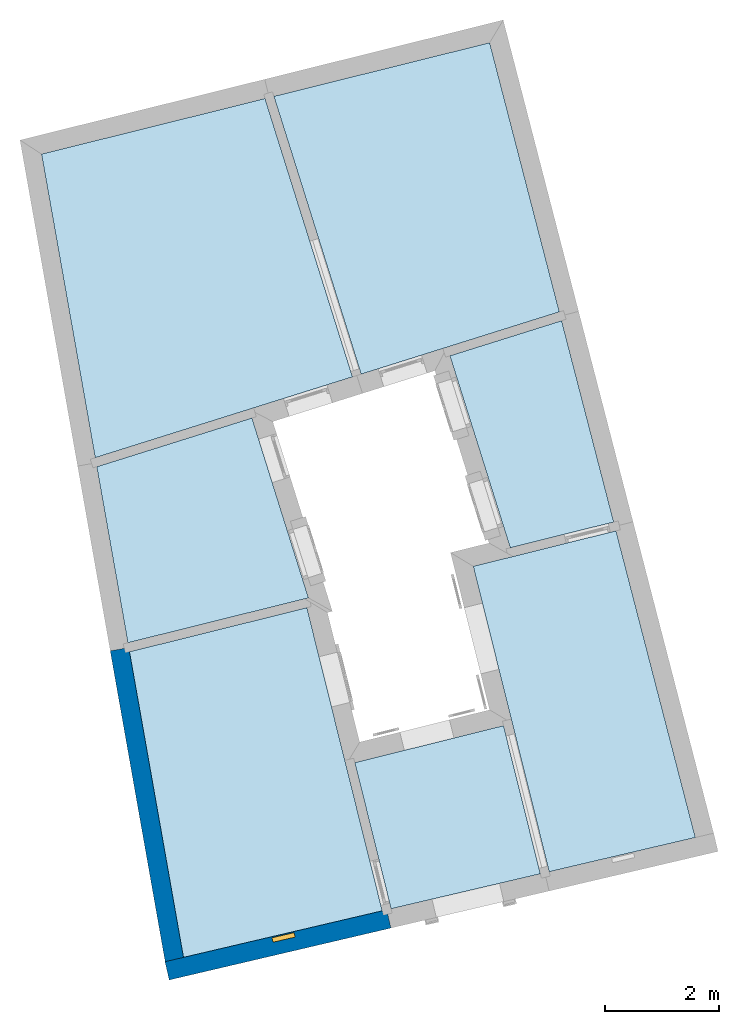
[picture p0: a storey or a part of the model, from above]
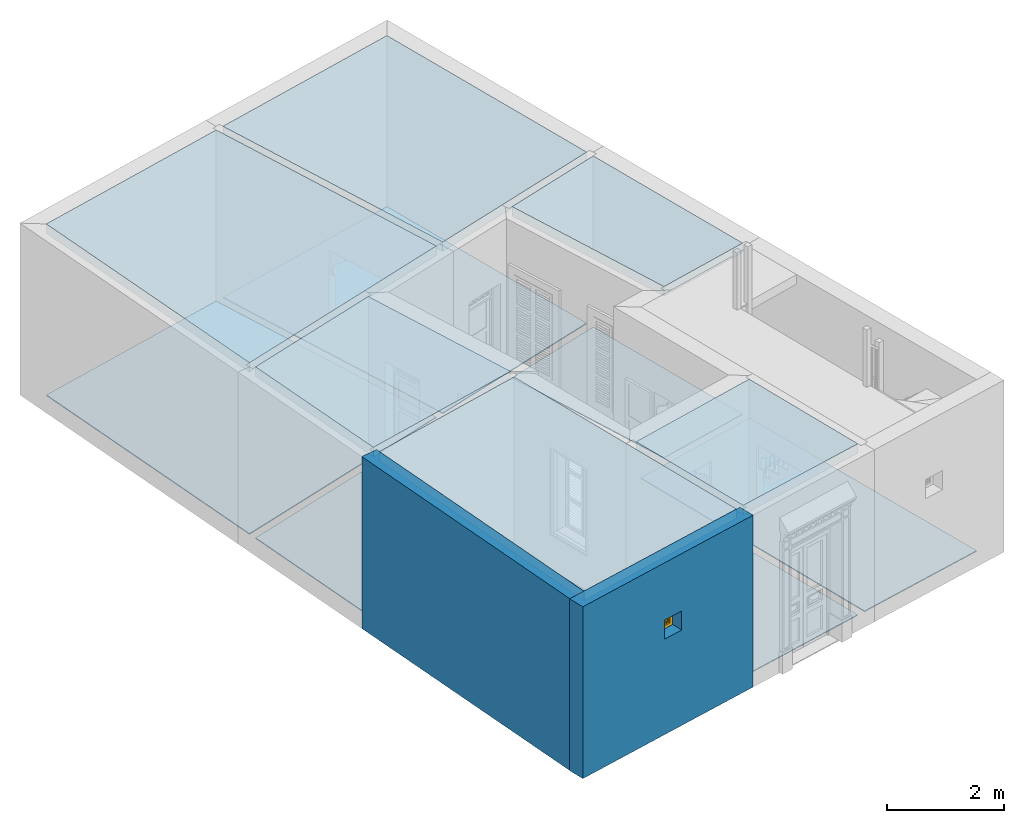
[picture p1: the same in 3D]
Properties of the parts of a building model (IFC4)

# File
Description: ViewDefinition[DesignTransferView]
File name: molior-ifc.pl
Time: 2024-09-23T22:30:47
Author: bruno
Written by: File::IFC-0.01

# IfcProject, Molior Project
Document: Building plot-0; plot-0 0; plot-0 1; Building plot-0 NORTH; Building plot-0 SOUTH; Building plot-0 WEST; Building plot-0 EAST; Building plot-0 LOCATION; Building plot-1; plot-1 0; plot-1 1; plot-1 2; Building plot-1 NORTH; Building plot-1 SOUTH; Building plot-1 WEST; Building plot-1 EAST; Building plot-1 LOCATION; Building plot-2; plot-2 0; plot-2 1; Building plot-2 NORTH; Building plot-2 SOUTH; Building plot-2 WEST; Building plot-2 EAST; Building plot-2 LOCATION; Building plot-3; plot-3 0; plot-3 1; Building plot-3 NORTH; Building plot-3 SOUTH; Building plot-3 WEST; Building plot-3 EAST; Building plot-3 LOCATION; Building plot-4; plot-4 0; plot-4 1; plot-4 2; Building plot-4 NORTH; Building plot-4 SOUTH; Building plot-4 WEST; Building plot-4 EAST; Building plot-4 LOCATION; Building plot-5; plot-5 0; plot-5 1; Building plot-5 NORTH; Building plot-5 SOUTH; Building plot-5 WEST; Building plot-5 EAST; Building plot-5 LOCATION; Building plot-6; plot-6 0; plot-6 1; Building plot-6 NORTH; Building plot-6 SOUTH; Building plot-6 WEST; Building plot-6 EAST; Building plot-6 LOCATION; Building plot-7; plot-7 0; plot-7 1; plot-7 2; Building plot-7 NORTH; Building plot-7 SOUTH; Building plot-7 WEST; Building plot-7 EAST; Building plot-7 LOCATION; Building plot-8; plot-8 0; plot-8 1; Building plot-8 NORTH; Building plot-8 SOUTH; Building plot-8 WEST; Building plot-8 EAST; Building plot-8 LOCATION; Building plot-9; plot-9 0; plot-9 1; Building plot-9 NORTH; Building plot-9 SOUTH; Building plot-9 WEST; Building plot-9 EAST; Building plot-9 LOCATION; Building plot-10; plot-10 0; plot-10 1; Building plot-10 NORTH; Building plot-10 SOUTH; Building plot-10 WEST; Building plot-10 EAST; Building plot-10 LOCATION

# IfcBuildingStorey (25)
Name | In | Elevation (m)
plot-0 0 | Building plot-0 | 0
plot-0 1 | Building plot-0 | 3.6
plot-1 0 | Building plot-1 | 0
plot-1 1 | Building plot-1 | 2.7
plot-1 2 | Building plot-1 | 5.4
plot-10 0 | Building plot-10 | 0
plot-10 1 | Building plot-10 | 2.7
plot-2 0 | Building plot-2 | 0
plot-2 1 | Building plot-2 | 2.85
plot-3 0 | Building plot-3 | 0
plot-3 1 | Building plot-3 | 3.3
plot-4 0 | Building plot-4 | 0
plot-4 1 | Building plot-4 | 2.7
plot-4 2 | Building plot-4 | 5.4
plot-5 0 | Building plot-5 | 0
plot-5 1 | Building plot-5 | 3.45
plot-6 0 | Building plot-6 | 0
plot-6 1 | Building plot-6 | 3.6
plot-7 0 | Building plot-7 | 0
plot-7 1 | Building plot-7 | 3
plot-7 2 | Building plot-7 | 5.7
plot-8 0 | Building plot-8 | 0
plot-8 1 | Building plot-8 | 3
plot-9 0 | Building plot-9 | 0
plot-9 1 | Building plot-9 | 2.85

# IfcSpace (168)
Name | In | LongName | PredefinedType | NetFloorArea (m2) | Height (m) | NetVolume (m3)
Bedroom | plot-0 0 | Bedroom 0 rl | INTERNAL | 18.6033 | 3.38 | 62.8793
Circulation | plot-0 0 | Circulation 0 rrrl | INTERNAL | 7.18052 | 3.38 | 24.2702
Sahn | plot-0 0 | Sahn 0 rrrr | EXTERNAL | 7.24061 | 3.38 | 24.4733
Bedroom | plot-0 0 | Bedroom 0 lll | INTERNAL | 9.86909 | 3.38 | 33.3575
Sahn | plot-0 0 | Sahn 0 llrr | EXTERNAL | 11.4049 | 3.38 | 38.5485
Living | plot-0 0 | Living 0 lrr | INTERNAL | 23.1098 | 3.38 | 78.1113
Toilet | plot-0 0 | Toilet 0 llrl | INTERNAL | 7.06812 | 3.38 | 23.8902
Kitchen | plot-0 0 | Kitchen 0 lrl | INTERNAL | 18.9053 | 3.38 | 63.9
Stair | plot-0 0 | Stair 0 rrl | INTERNAL | 14.5007 | 3.38 | 49.0124
Toilet | plot-0 1 | Toilet 1 llrl | INTERNAL | 7.06812 | 2.48 | 17.5289
Sahn | plot-0 1 | Sahn 1 lll | EXTERNAL | 9.86909 | 2.48 | 24.4753
Sahn | plot-0 1 | Sahn 1 rl | EXTERNAL | 18.6033 | 2.48 | 46.1363
Stair | plot-0 1 | Stair 1 rrl | INTERNAL | 14.5007 | 2.48 | 35.9617
Sahn | plot-0 1 | Sahn 1 rrrl | EXTERNAL | 7.18052 | 2.48 | 17.8077
Sahn | plot-0 1 | Sahn 1 lrrr | EXTERNAL | 10.2465 | 2.48 | 25.4112
Bedroom | plot-0 1 | Bedroom 1 lrl | INTERNAL | 18.9053 | 2.48 | 46.8852
Bedroom | plot-0 1 | Bedroom 1 lrrl | INTERNAL | 12.1528 | 2.48 | 30.139
Stair | plot-1 0 | Stair 0 rl | INTERNAL | 13.5087 | 2.48 | 33.5016
Bedroom | plot-1 0 | Bedroom 0 rr | INTERNAL | 15.269 | 2.48 | 37.8671
Sahn | plot-1 0 | Sahn 0 llll | EXTERNAL | 16.588 | 2.48 | 41.1382
Circulation | plot-1 0 | Circulation 0 llr | INTERNAL | 15.6253 | 2.48 | 38.7507
Bedroom | plot-1 0 | Bedroom 0 lllrr | INTERNAL | 7.61929 | 2.48 | 18.8958
Living | plot-1 0 | Living 0 lr | INTERNAL | 20.2347 | 2.48 | 50.1821
Toilet | plot-1 0 | Toilet 0 lllrl | INTERNAL | 7.64653 | 2.48 | 18.9634
Kitchen | plot-1 1 | Kitchen 1 lllrl | INTERNAL | 7.64653 | 2.48 | 18.9634
Bedroom | plot-1 1 | Bedroom 1 lllrr | INTERNAL | 7.61929 | 2.48 | 18.8958
Living | plot-1 1 | Living 1 lr | INTERNAL | 20.2347 | 2.48 | 50.1821
Stair | plot-1 1 | Stair 1 rl | INTERNAL | 13.5087 | 2.48 | 33.5016
Sahn | plot-1 1 | Sahn 1 rr | EXTERNAL | 15.269 | 2.48 | 37.8671
Sahn | plot-1 1 | Sahn 1 llr | EXTERNAL | 15.6253 | 2.48 | 38.7507
Sahn | plot-1 2 | Sahn 2 lllrl | EXTERNAL | 7.64653 | 2.48 | 18.9634
Sahn | plot-1 2 | Sahn 2 lllrr | EXTERNAL | 7.61929 | 2.48 | 18.8958
Sahn | plot-1 2 | Sahn 2 lr | EXTERNAL | 20.2347 | 2.48 | 50.1821
Stair | plot-1 2 | Stair 2 rl | INTERNAL | 13.5087 | 2.48 | 33.5016
Circulation | plot-10 0 | Circulation 0 lrlll | INTERNAL | 7.03777 | 2.48 | 17.4537
Toilet | plot-10 0 | Toilet 0 lrllr | INTERNAL | 8.32168 | 2.48 | 20.6378
Kitchen | plot-10 0 | Kitchen 0 lll | INTERNAL | 12.7723 | 2.48 | 31.6752
Bedroom | plot-10 0 | Bedroom 0 llr | INTERNAL | 13.3682 | 2.48 | 33.1531
Sahn | plot-10 0 | Sahn 0 lrlr | EXTERNAL | 14.0717 | 2.48 | 34.8977
Stair | plot-10 0 | Stair 0 lrr | INTERNAL | 10.8846 | 2.48 | 26.9937
Living | plot-10 0 | Living 0 r | INTERNAL | 23.0062 | 2.48 | 57.0555
Bedroom | plot-10 1 | Bedroom 1 lll | INTERNAL | 12.7723 | 2.48 | 31.6752
Sahn | plot-10 1 | Sahn 1 llr | EXTERNAL | 13.3682 | 2.48 | 33.1531
Stair | plot-10 1 | Stair 1 lrr | INTERNAL | 10.8846 | 2.48 | 26.9937
Living | plot-10 1 | Living 1 r | INTERNAL | 23.0062 | 2.48 | 57.0555
Sahn | plot-10 1 | Sahn 1 lrlll | EXTERNAL | 7.03777 | 2.48 | 17.4537
Sahn | plot-10 1 | Sahn 1 lrllr | EXTERNAL | 8.32168 | 2.48 | 20.6378
Sahn | plot-2 0 | Sahn 0 llll | EXTERNAL | 19.2153 | 2.63 | 50.5361
Stair | plot-2 0 | Stair 0 llrl | INTERNAL | 12.6232 | 2.63 | 33.1991
Kitchen | plot-2 0 | Kitchen 0 llrr | INTERNAL | 14.1375 | 2.63 | 37.1816
Toilet | plot-2 0 | Toilet 0 lllr | INTERNAL | 8.14435 | 2.63 | 21.4196
Circulation | plot-2 0 | Circulation 0 rl | INTERNAL | 18.3057 | 2.63 | 48.1441
Bedroom | plot-2 0 | Bedroom 0 rrl | INTERNAL | 5.66446 | 2.63 | 14.8975
Bedroom | plot-2 0 | Bedroom 0 rrr | INTERNAL | 11.2214 | 2.63 | 29.5124
Living | plot-2 0 | Living 0 lr | INTERNAL | 30.7366 | 2.63 | 80.8373
Sahn | plot-2 1 | Sahn 1 lllr | EXTERNAL | 8.14435 | 2.48 | 20.198
Sahn | plot-2 1 | Sahn 1 lrl | EXTERNAL | 18.1389 | 2.48 | 44.9844
Sahn | plot-2 1 | Sahn 1 llrr | EXTERNAL | 14.1375 | 2.48 | 35.061
Toilet | plot-2 1 | Toilet 1 lrrl | INTERNAL | 5.53656 | 2.48 | 13.7307
Bedroom | plot-2 1 | Bedroom 1 lrrr | INTERNAL | 5.7305 | 2.48 | 14.2116
Stair | plot-2 1 | Stair 1 llrl | INTERNAL | 12.6232 | 2.48 | 31.3056
Bedroom | plot-2 1 | Bedroom 1 rl | INTERNAL | 18.3057 | 2.48 | 45.3982
Bedroom | plot-2 1 | Bedroom 1 rr | INTERNAL | 17.3011 | 2.48 | 42.9068
Sahn | plot-3 0 | Sahn 0 rrll | EXTERNAL | 12.8553 | 3.08 | 39.5942
Living | plot-3 0 | Living 0 rrr | INTERNAL | 19.1901 | 3.08 | 59.1056
Kitchen | plot-3 0 | Kitchen 0 rrlrl | INTERNAL | 6.68529 | 3.08 | 20.5907
Bedroom | plot-3 0 | Bedroom 0 rl | INTERNAL | 17.7381 | 3.08 | 54.6334
Toilet | plot-3 0 | Toilet 0 rrlrr | INTERNAL | 6.24022 | 3.08 | 19.2199
Stair | plot-3 0 | Stair 0 ll | INTERNAL | 11.7867 | 3.08 | 36.303
Circulation | plot-3 0 | Circulation 0 lr | INTERNAL | 15.885 | 3.08 | 48.9257
Sahn | plot-3 1 | Sahn 1 rrlrl | EXTERNAL | 6.68529 | 2.48 | 16.5795
Circulation | plot-3 1 | Circulation 1 rrlrr | INTERNAL | 6.24022 | 2.48 | 15.4757
Stair | plot-3 1 | Stair 1 ll | INTERNAL | 11.7867 | 2.48 | 29.231
Sahn | plot-3 1 | Sahn 1 rl | EXTERNAL | 17.7381 | 2.48 | 43.9905
Bedroom | plot-3 1 | Bedroom 1 lrl | INTERNAL | 11.3691 | 2.48 | 28.1954
Sahn | plot-3 1 | Sahn 1 rrr | EXTERNAL | 19.1901 | 2.48 | 47.5916
Bedroom | plot-3 1 | Bedroom 1 lrr | INTERNAL | 4.17706 | 2.48 | 10.3591
Circulation | plot-4 0 | Circulation 0 lllllr | INTERNAL | 5.30634 | 2.48 | 13.1597
Toilet | plot-4 0 | Toilet 0 llllr | INTERNAL | 7.85125 | 2.48 | 19.4711
Kitchen | plot-4 0 | Kitchen 0 rl | INTERNAL | 14.8165 | 2.48 | 36.7448
Living | plot-4 0 | Living 0 rr | INTERNAL | 23.3067 | 2.48 | 57.8006
Sahn | plot-4 0 | Sahn 0 lllr | EXTERNAL | 20.2577 | 2.48 | 50.239
Stair | plot-4 0 | Stair 0 lrl | INTERNAL | 11.632 | 2.48 | 28.8474
Toilet | plot-4 0 | Toilet 0 llllll | INTERNAL | 6.71825 | 2.48 | 16.6613
Bedroom | plot-4 0 | Bedroom 0 llr | INTERNAL | 19.073 | 2.48 | 47.3011
Bedroom | plot-4 0 | Bedroom 0 lrr | INTERNAL | 13.8841 | 2.48 | 34.4327
Bedroom | plot-4 1 | Bedroom 1 rl | INTERNAL | 14.8165 | 2.48 | 36.7448
Living | plot-4 1 | Living 1 rr | INTERNAL | 23.3067 | 2.48 | 57.8006
Sahn | plot-4 1 | Sahn 1 lllllr | EXTERNAL | 5.30634 | 2.48 | 13.1597
Sahn | plot-4 1 | Sahn 1 llllr | EXTERNAL | 7.85125 | 2.48 | 19.4711
Sahn | plot-4 1 | Sahn 1 llllll | EXTERNAL | 6.71825 | 2.48 | 16.6613
Stair | plot-4 1 | Stair 1 lrl | INTERNAL | 11.632 | 2.48 | 28.8474
Sahn | plot-4 1 | Sahn 1 lrr | EXTERNAL | 13.8841 | 2.48 | 34.4327
Sahn | plot-4 1 | Sahn 1 llr | EXTERNAL | 19.073 | 2.48 | 47.3011
Bedroom | plot-4 2 | Bedroom 2 rl | INTERNAL | 14.8165 | 2.48 | 36.7448
Sahn | plot-4 2 | Sahn 2 rr | EXTERNAL | 23.3067 | 2.48 | 57.8006
Stair | plot-4 2 | Stair 2 lrl | INTERNAL | 11.632 | 2.48 | 28.8474
Kitchen | plot-5 0 | Kitchen 0 rlll | INTERNAL | 8.13273 | 3.23 | 26.2687
Stair | plot-5 0 | Stair 0 rr | INTERNAL | 15.9944 | 3.23 | 51.662
Sahn | plot-5 0 | Sahn 0 rllr | EXTERNAL | 7.58685 | 3.23 | 24.5055
Bedroom | plot-5 0 | Bedroom 0 ll | INTERNAL | 14.4939 | 3.23 | 46.8152
Circulation | plot-5 0 | Circulation 0 lr | INTERNAL | 13.1461 | 3.23 | 42.462
Living | plot-5 0 | Living 0 rlr | INTERNAL | 18.2042 | 3.23 | 58.7996
Sahn | plot-5 1 | Sahn 1 lrl | EXTERNAL | 6.59347 | 2.48 | 16.3518
Toilet | plot-5 1 | Toilet 1 lrr | INTERNAL | 6.14669 | 2.48 | 15.2438
Sahn | plot-5 1 | Sahn 1 ll | EXTERNAL | 14.4939 | 2.48 | 35.9448
Sahn | plot-5 1 | Sahn 1 rlll | EXTERNAL | 8.13273 | 2.48 | 20.1692
Stair | plot-5 1 | Stair 1 rr | INTERNAL | 15.9944 | 2.48 | 39.6662
Bedroom | plot-5 1 | Bedroom 1 rlr | INTERNAL | 18.2042 | 2.48 | 45.1464
Sahn | plot-6 0 | Sahn 0 llll | EXTERNAL | 12.5452 | 3.38 | 42.4029
Bedroom | plot-6 0 | Bedroom 0 rl | INTERNAL | 11.0626 | 3.38 | 37.3915
Bedroom | plot-6 0 | Bedroom 0 rr | INTERNAL | 11.039 | 3.38 | 37.3117
Toilet | plot-6 0 | Toilet 0 lllr | INTERNAL | 7.05394 | 3.38 | 23.8423
Stair | plot-6 0 | Stair 0 lr | INTERNAL | 13.6163 | 3.38 | 46.0231
Circulation | plot-6 0 | Circulation 0 llr | INTERNAL | 18.765 | 3.38 | 63.4256
Bedroom | plot-6 1 | Bedroom 1 rl | INTERNAL | 11.0626 | 2.48 | 27.4352
Sahn | plot-6 1 | Sahn 1 rr | EXTERNAL | 11.039 | 2.48 | 27.3766
Kitchen | plot-6 1 | Kitchen 1 lllr | INTERNAL | 7.05394 | 2.48 | 17.4938
Stair | plot-6 1 | Stair 1 lr | INTERNAL | 13.6163 | 2.48 | 33.7685
Living | plot-6 1 | Living 1 llr | INTERNAL | 18.765 | 2.48 | 46.5371
Toilet | plot-7 0 | Toilet 0 rlrl | INTERNAL | 3.98221 | 2.78 | 11.0705
Toilet | plot-7 0 | Toilet 0 rlrr | INTERNAL | 5.86152 | 2.78 | 16.295
Sahn | plot-7 0 | Sahn 0 rll | EXTERNAL | 8.14408 | 2.78 | 22.6406
Circulation | plot-7 0 | Circulation 0 lrl | INTERNAL | 12.4041 | 2.78 | 34.4834
Kitchen | plot-7 0 | Kitchen 0 lrr | INTERNAL | 12.9413 | 2.78 | 35.9769
Stair | plot-7 0 | Stair 0 ll | INTERNAL | 10.553 | 2.78 | 29.3373
Living | plot-7 0 | Living 0 rr | INTERNAL | 14.6748 | 2.78 | 40.7959
Sahn | plot-7 1 | Sahn 1 rlrl | EXTERNAL | 3.98221 | 2.48 | 9.87588
Sahn | plot-7 1 | Sahn 1 rlrr | EXTERNAL | 5.86152 | 2.48 | 14.5366
Bedroom | plot-7 1 | Bedroom 1 lrl | INTERNAL | 12.4041 | 2.48 | 30.7622
Sahn | plot-7 1 | Sahn 1 lrr | EXTERNAL | 12.9413 | 2.48 | 32.0945
Stair | plot-7 1 | Stair 1 ll | INTERNAL | 10.553 | 2.48 | 26.1714
Sahn | plot-7 1 | Sahn 1 rr | EXTERNAL | 14.6748 | 2.48 | 36.3935
Stair | plot-7 2 | Stair 2 ll | INTERNAL | 10.553 | 2.48 | 26.1714
Bedroom | plot-7 2 | Bedroom 2 lrl | INTERNAL | 12.4041 | 2.48 | 30.7622
Living | plot-8 0 | Living 0 ll | INTERNAL | 17.9999 | 2.78 | 50.0396
Sahn | plot-8 0 | Sahn 0 rrrl | EXTERNAL | 18.5938 | 2.78 | 51.6907
Bedroom | plot-8 0 | Bedroom 0 rrrrr | INTERNAL | 11.8045 | 2.78 | 32.8164
Kitchen | plot-8 0 | Kitchen 0 lr | INTERNAL | 14.4188 | 2.78 | 40.0843
Toilet | plot-8 0 | Toilet 0 rll | INTERNAL | 10.7814 | 2.78 | 29.9723
Circulation | plot-8 0 | Circulation 0 rlr | INTERNAL | 12.9269 | 2.78 | 35.9368
Stair | plot-8 0 | Stair 0 rrl | INTERNAL | 12.6416 | 2.78 | 35.1437
Bedroom | plot-8 0 | Bedroom 0 rrrrl | INTERNAL | 7.50273 | 2.78 | 20.8576
Sahn | plot-8 1 | Sahn 1 rll | EXTERNAL | 10.7814 | 2.48 | 26.7379
Sahn | plot-8 1 | Sahn 1 rlr | EXTERNAL | 12.9269 | 2.48 | 32.0587
Stair | plot-8 1 | Stair 1 rrl | INTERNAL | 12.6416 | 2.48 | 31.3512
Sahn | plot-8 1 | Sahn 1 rrrrl | EXTERNAL | 7.50273 | 2.48 | 18.6068
Sahn | plot-8 1 | Sahn 1 rrrrr | EXTERNAL | 11.8045 | 2.48 | 29.2751
Bedroom | plot-8 1 | Bedroom 1 ll | INTERNAL | 17.9999 | 2.48 | 44.6397
Bedroom | plot-8 1 | Bedroom 1 lr | INTERNAL | 14.4188 | 2.48 | 35.7587
Bedroom | plot-9 0 | Bedroom 0 lrl | INTERNAL | 15.7746 | 2.63 | 41.4872
Bedroom | plot-9 0 | Bedroom 0 lrrl | INTERNAL | 6.73831 | 2.63 | 17.7218
Sahn | plot-9 0 | Sahn 0 lrrr | EXTERNAL | 9.66377 | 2.63 | 25.4157
Sahn | plot-9 0 | Sahn 0 lll | EXTERNAL | 11.3479 | 2.63 | 29.8449
Living | plot-9 0 | Living 0 rl | INTERNAL | 26.9561 | 2.63 | 70.8944
Kitchen | plot-9 0 | Kitchen 0 rr | INTERNAL | 22.585 | 2.63 | 59.3986
Toilet | plot-9 0 | Toilet 0 llrl | INTERNAL | 11.2217 | 2.63 | 29.5132
Stair | plot-9 0 | Stair 0 llrr | INTERNAL | 10.0608 | 2.63 | 26.4598
Sahn | plot-9 1 | Sahn 1 rll | EXTERNAL | 9.74117 | 2.48 | 24.1581
Bedroom | plot-9 1 | Bedroom 1 rlrl | INTERNAL | 8.31016 | 2.48 | 20.6092
Circulation | plot-9 1 | Circulation 1 rlrrl | INTERNAL | 3.32315 | 2.48 | 8.24141
Bedroom | plot-9 1 | Bedroom 1 lrrl | INTERNAL | 6.73831 | 2.48 | 16.711
Bedroom | plot-9 1 | Bedroom 1 llrl | INTERNAL | 11.2217 | 2.48 | 27.8299
Stair | plot-9 1 | Stair 1 llrr | INTERNAL | 10.0608 | 2.48 | 24.9507
Sahn | plot-9 1 | Sahn 1 rrl | EXTERNAL | 11.4975 | 2.48 | 28.5139
Circulation | plot-9 1 | Circulation 1 rrr | INTERNAL | 10.5731 | 2.48 | 26.2212
Sahn | plot-9 1 | Sahn 1 lrl | EXTERNAL | 15.7746 | 2.48 | 39.121
Bedroom | plot-9 1 | Bedroom 1 rlrrr | INTERNAL | 4.0163 | 2.48 | 9.96043

# IfcAnnotation: DRAWING (80)
EPset_Drawing - HasUnderlay: no; HasLinework: yes; HasAnnotation: yes; GlobalReferencing: yes; Stylesheet: drawings/assets/default.css; Markers: drawings/assets/markers.svg; Symbols: drawings/assets/symbols.svg; Patterns: drawings/assets/patterns.svg; ShadingStyles: drawings/assets/shading_styles.json; CurrentShadingStyle: Blender Default
Name | Document | TargetView | Scale | HumanScale | PositionX | PositionY | Group | Include
plot-0 0 | drawings/plot-0 0.svg drawings/plot-0 0.svg | PLAN_VIEW | 1/100 | 1:100 | 30 | 30 | plot-0 0
plot-0 1 | drawings/plot-0 1.svg drawings/plot-0 1.svg | PLAN_VIEW | 1/100 | 1:100 | 198.725 | 30 | plot-0 1
Building plot-0 NORTH | drawings/Building plot-0 NORTH.svg drawings/Building plot-0 NORTH.svg | ELEVATION_VIEW | 1/100 | 1:100 | 30 | 252.284 | Building plot-0 NORTH | IfcTypeProduct, IfcProduct, location="Building plot-0"
Building plot-0 SOUTH | drawings/Building plot-0 SOUTH.svg drawings/Building plot-0 SOUTH.svg | ELEVATION_VIEW | 1/100 | 1:100 | 198.725 | 252.284 | Building plot-0 SOUTH | IfcTypeProduct, IfcProduct, location="Building plot-0"
Building plot-0 WEST | drawings/Building plot-0 WEST.svg drawings/Building plot-0 WEST.svg | ELEVATION_VIEW | 1/100 | 1:100 | 367.45 | 252.284 | Building plot-0 WEST | IfcTypeProduct, IfcProduct, location="Building plot-0"
Building plot-0 EAST | drawings/Building plot-0 EAST.svg drawings/Building plot-0 EAST.svg | ELEVATION_VIEW | 1/100 | 1:100 | 579.733 | 252.284 | Building plot-0 EAST | IfcTypeProduct, IfcProduct, location="Building plot-0"
Building plot-0 LOCATION | drawings/Building plot-0 LOCATION.svg drawings/Building plot-0 LOCATION.svg | PLAN_VIEW | 1/1000 | 1:1000 | 792.017 | 252.284 | Building plot-0 LOCATION | IfcSite + IfcRoof, IfcWall, IfcSlab, location="Building plot-0"
plot-1 0 | drawings/plot-1 0.svg drawings/plot-1 0.svg | PLAN_VIEW | 1/100 | 1:100 | 30 | 30 | plot-1 0
plot-1 1 | drawings/plot-1 1.svg drawings/plot-1 1.svg | PLAN_VIEW | 1/100 | 1:100 | 202.963 | 30 | plot-1 1
plot-1 2 | drawings/plot-1 2.svg drawings/plot-1 2.svg | PLAN_VIEW | 1/100 | 1:100 | 375.926 | 30 | plot-1 2
Building plot-1 NORTH | drawings/Building plot-1 NORTH.svg drawings/Building plot-1 NORTH.svg | ELEVATION_VIEW | 1/100 | 1:100 | 30 | 221.306 | Building plot-1 NORTH | IfcTypeProduct, IfcProduct, location="Building plot-1"
Building plot-1 SOUTH | drawings/Building plot-1 SOUTH.svg drawings/Building plot-1 SOUTH.svg | ELEVATION_VIEW | 1/100 | 1:100 | 202.963 | 221.306 | Building plot-1 SOUTH | IfcTypeProduct, IfcProduct, location="Building plot-1"
Building plot-1 WEST | drawings/Building plot-1 WEST.svg drawings/Building plot-1 WEST.svg | ELEVATION_VIEW | 1/100 | 1:100 | 375.926 | 221.306 | Building plot-1 WEST | IfcTypeProduct, IfcProduct, location="Building plot-1"
Building plot-1 EAST | drawings/Building plot-1 EAST.svg drawings/Building plot-1 EAST.svg | ELEVATION_VIEW | 1/100 | 1:100 | 557.232 | 221.306 | Building plot-1 EAST | IfcTypeProduct, IfcProduct, location="Building plot-1"
Building plot-1 LOCATION | drawings/Building plot-1 LOCATION.svg drawings/Building plot-1 LOCATION.svg | PLAN_VIEW | 1/1000 | 1:1000 | 738.538 | 221.306 | Building plot-1 LOCATION | IfcSite + IfcRoof, IfcWall, IfcSlab, location="Building plot-1"
plot-2 0 | drawings/plot-2 0.svg drawings/plot-2 0.svg | PLAN_VIEW | 1/100 | 1:100 | 30 | 30 | plot-2 0
plot-2 1 | drawings/plot-2 1.svg drawings/plot-2 1.svg | PLAN_VIEW | 1/100 | 1:100 | 207.942 | 30 | plot-2 1
Building plot-2 NORTH | drawings/Building plot-2 NORTH.svg drawings/Building plot-2 NORTH.svg | ELEVATION_VIEW | 1/100 | 1:100 | 30 | 245.056 | Building plot-2 NORTH | IfcTypeProduct, IfcProduct, location="Building plot-2"
Building plot-2 SOUTH | drawings/Building plot-2 SOUTH.svg drawings/Building plot-2 SOUTH.svg | ELEVATION_VIEW | 1/100 | 1:100 | 207.942 | 245.056 | Building plot-2 SOUTH | IfcTypeProduct, IfcProduct, location="Building plot-2"
Building plot-2 WEST | drawings/Building plot-2 WEST.svg drawings/Building plot-2 WEST.svg | ELEVATION_VIEW | 1/100 | 1:100 | 385.883 | 245.056 | Building plot-2 WEST | IfcTypeProduct, IfcProduct, location="Building plot-2"
Building plot-2 EAST | drawings/Building plot-2 EAST.svg drawings/Building plot-2 EAST.svg | ELEVATION_VIEW | 1/100 | 1:100 | 590.939 | 245.056 | Building plot-2 EAST | IfcTypeProduct, IfcProduct, location="Building plot-2"
Building plot-2 LOCATION | drawings/Building plot-2 LOCATION.svg drawings/Building plot-2 LOCATION.svg | PLAN_VIEW | 1/1000 | 1:1000 | 795.996 | 245.056 | Building plot-2 LOCATION | IfcSite + IfcRoof, IfcWall, IfcSlab, location="Building plot-2"
plot-3 0 | drawings/plot-3 0.svg drawings/plot-3 0.svg | PLAN_VIEW | 1/100 | 1:100 | 30 | 30 | plot-3 0
plot-3 1 | drawings/plot-3 1.svg drawings/plot-3 1.svg | PLAN_VIEW | 1/100 | 1:100 | 183.355 | 30 | plot-3 1
Building plot-3 NORTH | drawings/Building plot-3 NORTH.svg drawings/Building plot-3 NORTH.svg | ELEVATION_VIEW | 1/100 | 1:100 | 30 | 244.792 | Building plot-3 NORTH | IfcTypeProduct, IfcProduct, location="Building plot-3"
Building plot-3 SOUTH | drawings/Building plot-3 SOUTH.svg drawings/Building plot-3 SOUTH.svg | ELEVATION_VIEW | 1/100 | 1:100 | 183.355 | 244.792 | Building plot-3 SOUTH | IfcTypeProduct, IfcProduct, location="Building plot-3"
Building plot-3 WEST | drawings/Building plot-3 WEST.svg drawings/Building plot-3 WEST.svg | ELEVATION_VIEW | 1/100 | 1:100 | 336.71 | 244.792 | Building plot-3 WEST | IfcTypeProduct, IfcProduct, location="Building plot-3"
Building plot-3 EAST | drawings/Building plot-3 EAST.svg drawings/Building plot-3 EAST.svg | ELEVATION_VIEW | 1/100 | 1:100 | 541.501 | 244.792 | Building plot-3 EAST | IfcTypeProduct, IfcProduct, location="Building plot-3"
Building plot-3 LOCATION | drawings/Building plot-3 LOCATION.svg drawings/Building plot-3 LOCATION.svg | PLAN_VIEW | 1/1000 | 1:1000 | 746.293 | 244.792 | Building plot-3 LOCATION | IfcSite + IfcRoof, IfcWall, IfcSlab, location="Building plot-3"
plot-4 0 | drawings/plot-4 0.svg drawings/plot-4 0.svg | PLAN_VIEW | 1/100 | 1:100 | 30 | 30 | plot-4 0
plot-4 1 | drawings/plot-4 1.svg drawings/plot-4 1.svg | PLAN_VIEW | 1/100 | 1:100 | 199.8 | 30 | plot-4 1
plot-4 2 | drawings/plot-4 2.svg drawings/plot-4 2.svg | PLAN_VIEW | 1/100 | 1:100 | 369.601 | 30 | plot-4 2
Building plot-4 NORTH | drawings/Building plot-4 NORTH.svg drawings/Building plot-4 NORTH.svg | ELEVATION_VIEW | 1/100 | 1:100 | 30 | 268.923 | Building plot-4 NORTH | IfcTypeProduct, IfcProduct, location="Building plot-4"
Building plot-4 SOUTH | drawings/Building plot-4 SOUTH.svg drawings/Building plot-4 SOUTH.svg | ELEVATION_VIEW | 1/100 | 1:100 | 199.8 | 268.923 | Building plot-4 SOUTH | IfcTypeProduct, IfcProduct, location="Building plot-4"
Building plot-4 WEST | drawings/Building plot-4 WEST.svg drawings/Building plot-4 WEST.svg | ELEVATION_VIEW | 1/100 | 1:100 | 369.601 | 268.923 | Building plot-4 WEST | IfcTypeProduct, IfcProduct, location="Building plot-4"
Building plot-4 EAST | drawings/Building plot-4 EAST.svg drawings/Building plot-4 EAST.svg | ELEVATION_VIEW | 1/100 | 1:100 | 598.523 | 268.923 | Building plot-4 EAST | IfcTypeProduct, IfcProduct, location="Building plot-4"
Building plot-4 LOCATION | drawings/Building plot-4 LOCATION.svg drawings/Building plot-4 LOCATION.svg | PLAN_VIEW | 1/1000 | 1:1000 | 827.446 | 268.923 | Building plot-4 LOCATION | IfcSite + IfcRoof, IfcWall, IfcSlab, location="Building plot-4"
plot-5 0 | drawings/plot-5 0.svg drawings/plot-5 0.svg | PLAN_VIEW | 1/100 | 1:100 | 30 | 30 | plot-5 0
plot-5 1 | drawings/plot-5 1.svg drawings/plot-5 1.svg | PLAN_VIEW | 1/100 | 1:100 | 187.814 | 30 | plot-5 1
Building plot-5 NORTH | drawings/Building plot-5 NORTH.svg drawings/Building plot-5 NORTH.svg | ELEVATION_VIEW | 1/100 | 1:100 | 30 | 212.661 | Building plot-5 NORTH | IfcTypeProduct, IfcProduct, location="Building plot-5"
Building plot-5 SOUTH | drawings/Building plot-5 SOUTH.svg drawings/Building plot-5 SOUTH.svg | ELEVATION_VIEW | 1/100 | 1:100 | 187.814 | 212.661 | Building plot-5 SOUTH | IfcTypeProduct, IfcProduct, location="Building plot-5"
Building plot-5 WEST | drawings/Building plot-5 WEST.svg drawings/Building plot-5 WEST.svg | ELEVATION_VIEW | 1/100 | 1:100 | 345.628 | 212.661 | Building plot-5 WEST | IfcTypeProduct, IfcProduct, location="Building plot-5"
Building plot-5 EAST | drawings/Building plot-5 EAST.svg drawings/Building plot-5 EAST.svg | ELEVATION_VIEW | 1/100 | 1:100 | 518.289 | 212.661 | Building plot-5 EAST | IfcTypeProduct, IfcProduct, location="Building plot-5"
Building plot-5 LOCATION | drawings/Building plot-5 LOCATION.svg drawings/Building plot-5 LOCATION.svg | PLAN_VIEW | 1/1000 | 1:1000 | 690.95 | 212.661 | Building plot-5 LOCATION | IfcSite + IfcRoof, IfcWall, IfcSlab, location="Building plot-5"
plot-6 0 | drawings/plot-6 0.svg drawings/plot-6 0.svg | PLAN_VIEW | 1/100 | 1:100 | 30 | 30 | plot-6 0
plot-6 1 | drawings/plot-6 1.svg drawings/plot-6 1.svg | PLAN_VIEW | 1/100 | 1:100 | 203.312 | 30 | plot-6 1
Building plot-6 NORTH | drawings/Building plot-6 NORTH.svg drawings/Building plot-6 NORTH.svg | ELEVATION_VIEW | 1/100 | 1:100 | 30 | 184.666 | Building plot-6 NORTH | IfcTypeProduct, IfcProduct, location="Building plot-6"
Building plot-6 SOUTH | drawings/Building plot-6 SOUTH.svg drawings/Building plot-6 SOUTH.svg | ELEVATION_VIEW | 1/100 | 1:100 | 203.312 | 184.666 | Building plot-6 SOUTH | IfcTypeProduct, IfcProduct, location="Building plot-6"
Building plot-6 WEST | drawings/Building plot-6 WEST.svg drawings/Building plot-6 WEST.svg | ELEVATION_VIEW | 1/100 | 1:100 | 376.623 | 184.666 | Building plot-6 WEST | IfcTypeProduct, IfcProduct, location="Building plot-6"
Building plot-6 EAST | drawings/Building plot-6 EAST.svg drawings/Building plot-6 EAST.svg | ELEVATION_VIEW | 1/100 | 1:100 | 521.29 | 184.666 | Building plot-6 EAST | IfcTypeProduct, IfcProduct, location="Building plot-6"
Building plot-6 LOCATION | drawings/Building plot-6 LOCATION.svg drawings/Building plot-6 LOCATION.svg | PLAN_VIEW | 1/1000 | 1:1000 | 665.956 | 184.666 | Building plot-6 LOCATION | IfcSite + IfcRoof, IfcWall, IfcSlab, location="Building plot-6"
plot-7 0 | drawings/plot-7 0.svg drawings/plot-7 0.svg | PLAN_VIEW | 1/100 | 1:100 | 30 | 30 | plot-7 0
plot-7 1 | drawings/plot-7 1.svg drawings/plot-7 1.svg | PLAN_VIEW | 1/100 | 1:100 | 202.126 | 30 | plot-7 1
plot-7 2 | drawings/plot-7 2.svg drawings/plot-7 2.svg | PLAN_VIEW | 1/100 | 1:100 | 374.253 | 30 | plot-7 2
Building plot-7 NORTH | drawings/Building plot-7 NORTH.svg drawings/Building plot-7 NORTH.svg | ELEVATION_VIEW | 1/100 | 1:100 | 30 | 179.359 | Building plot-7 NORTH | IfcTypeProduct, IfcProduct, location="Building plot-7"
Building plot-7 SOUTH | drawings/Building plot-7 SOUTH.svg drawings/Building plot-7 SOUTH.svg | ELEVATION_VIEW | 1/100 | 1:100 | 202.126 | 179.359 | Building plot-7 SOUTH | IfcTypeProduct, IfcProduct, location="Building plot-7"
Building plot-7 WEST | drawings/Building plot-7 WEST.svg drawings/Building plot-7 WEST.svg | ELEVATION_VIEW | 1/100 | 1:100 | 374.253 | 179.359 | Building plot-7 WEST | IfcTypeProduct, IfcProduct, location="Building plot-7"
Building plot-7 EAST | drawings/Building plot-7 EAST.svg drawings/Building plot-7 EAST.svg | ELEVATION_VIEW | 1/100 | 1:100 | 513.612 | 179.359 | Building plot-7 EAST | IfcTypeProduct, IfcProduct, location="Building plot-7"
Building plot-7 LOCATION | drawings/Building plot-7 LOCATION.svg drawings/Building plot-7 LOCATION.svg | PLAN_VIEW | 1/1000 | 1:1000 | 652.971 | 179.359 | Building plot-7 LOCATION | IfcSite + IfcRoof, IfcWall, IfcSlab, location="Building plot-7"
plot-8 0 | drawings/plot-8 0.svg drawings/plot-8 0.svg | PLAN_VIEW | 1/100 | 1:100 | 30 | 30 | plot-8 0
plot-8 1 | drawings/plot-8 1.svg drawings/plot-8 1.svg | PLAN_VIEW | 1/100 | 1:100 | 215.568 | 30 | plot-8 1
Building plot-8 NORTH | drawings/Building plot-8 NORTH.svg drawings/Building plot-8 NORTH.svg | ELEVATION_VIEW | 1/100 | 1:100 | 30 | 224.068 | Building plot-8 NORTH | IfcTypeProduct, IfcProduct, location="Building plot-8"
Building plot-8 SOUTH | drawings/Building plot-8 SOUTH.svg drawings/Building plot-8 SOUTH.svg | ELEVATION_VIEW | 1/100 | 1:100 | 215.568 | 224.068 | Building plot-8 SOUTH | IfcTypeProduct, IfcProduct, location="Building plot-8"
Building plot-8 WEST | drawings/Building plot-8 WEST.svg drawings/Building plot-8 WEST.svg | ELEVATION_VIEW | 1/100 | 1:100 | 401.137 | 224.068 | Building plot-8 WEST | IfcTypeProduct, IfcProduct, location="Building plot-8"
Building plot-8 EAST | drawings/Building plot-8 EAST.svg drawings/Building plot-8 EAST.svg | ELEVATION_VIEW | 1/100 | 1:100 | 585.205 | 224.068 | Building plot-8 EAST | IfcTypeProduct, IfcProduct, location="Building plot-8"
Building plot-8 LOCATION | drawings/Building plot-8 LOCATION.svg drawings/Building plot-8 LOCATION.svg | PLAN_VIEW | 1/1000 | 1:1000 | 769.273 | 224.068 | Building plot-8 LOCATION | IfcSite + IfcRoof, IfcWall, IfcSlab, location="Building plot-8"
plot-9 0 | drawings/plot-9 0.svg drawings/plot-9 0.svg | PLAN_VIEW | 1/100 | 1:100 | 30 | 30 | plot-9 0
plot-9 1 | drawings/plot-9 1.svg drawings/plot-9 1.svg | PLAN_VIEW | 1/100 | 1:100 | 193.283 | 30 | plot-9 1
Building plot-9 NORTH | drawings/Building plot-9 NORTH.svg drawings/Building plot-9 NORTH.svg | ELEVATION_VIEW | 1/100 | 1:100 | 30 | 250.638 | Building plot-9 NORTH | IfcTypeProduct, IfcProduct, location="Building plot-9"
Building plot-9 SOUTH | drawings/Building plot-9 SOUTH.svg drawings/Building plot-9 SOUTH.svg | ELEVATION_VIEW | 1/100 | 1:100 | 193.283 | 250.638 | Building plot-9 SOUTH | IfcTypeProduct, IfcProduct, location="Building plot-9"
Building plot-9 WEST | drawings/Building plot-9 WEST.svg drawings/Building plot-9 WEST.svg | ELEVATION_VIEW | 1/100 | 1:100 | 356.565 | 250.638 | Building plot-9 WEST | IfcTypeProduct, IfcProduct, location="Building plot-9"
Building plot-9 EAST | drawings/Building plot-9 EAST.svg drawings/Building plot-9 EAST.svg | ELEVATION_VIEW | 1/100 | 1:100 | 567.203 | 250.638 | Building plot-9 EAST | IfcTypeProduct, IfcProduct, location="Building plot-9"
Building plot-9 LOCATION | drawings/Building plot-9 LOCATION.svg drawings/Building plot-9 LOCATION.svg | PLAN_VIEW | 1/1000 | 1:1000 | 777.841 | 250.638 | Building plot-9 LOCATION | IfcSite + IfcRoof, IfcWall, IfcSlab, location="Building plot-9"
plot-10 0 | drawings/plot-10 0.svg drawings/plot-10 0.svg | PLAN_VIEW | 1/100 | 1:100 | 30 | 30 | plot-10 0
plot-10 1 | drawings/plot-10 1.svg drawings/plot-10 1.svg | PLAN_VIEW | 1/100 | 1:100 | 183.874 | 30 | plot-10 1
Building plot-10 NORTH | drawings/Building plot-10 NORTH.svg drawings/Building plot-10 NORTH.svg | ELEVATION_VIEW | 1/100 | 1:100 | 30 | 222.452 | Building plot-10 NORTH | IfcTypeProduct, IfcProduct, location="Building plot-10"
Building plot-10 SOUTH | drawings/Building plot-10 SOUTH.svg drawings/Building plot-10 SOUTH.svg | ELEVATION_VIEW | 1/100 | 1:100 | 183.874 | 222.452 | Building plot-10 SOUTH | IfcTypeProduct, IfcProduct, location="Building plot-10"
Building plot-10 WEST | drawings/Building plot-10 WEST.svg drawings/Building plot-10 WEST.svg | ELEVATION_VIEW | 1/100 | 1:100 | 337.749 | 222.452 | Building plot-10 WEST | IfcTypeProduct, IfcProduct, location="Building plot-10"
Building plot-10 EAST | drawings/Building plot-10 EAST.svg drawings/Building plot-10 EAST.svg | ELEVATION_VIEW | 1/100 | 1:100 | 520.201 | 222.452 | Building plot-10 EAST | IfcTypeProduct, IfcProduct, location="Building plot-10"
Building plot-10 LOCATION | drawings/Building plot-10 LOCATION.svg drawings/Building plot-10 LOCATION.svg | PLAN_VIEW | 1/1000 | 1:1000 | 702.653 | 222.452 | Building plot-10 LOCATION | IfcSite + IfcRoof, IfcWall, IfcSlab, location="Building plot-10"

# IfcAnnotation: TEXT (168)
EPset_Annotation - Classes: header
Name | Group
9 x TEXT | plot-0 0
8 x TEXT | plot-0 1
7 x TEXT | plot-1 0
6 x TEXT | plot-1 1
4 x TEXT | plot-1 2
8 x TEXT | plot-2 0
8 x TEXT | plot-2 1
7 x TEXT | plot-3 0
7 x TEXT | plot-3 1
9 x TEXT | plot-4 0
8 x TEXT | plot-4 1
3 x TEXT | plot-4 2
6 x TEXT | plot-5 0
6 x TEXT | plot-5 1
6 x TEXT | plot-6 0
5 x TEXT | plot-6 1
7 x TEXT | plot-7 0
6 x TEXT | plot-7 1
2 x TEXT | plot-7 2
8 x TEXT | plot-8 0
7 x TEXT | plot-8 1
8 x TEXT | plot-9 0
10 x TEXT | plot-9 1
7 x TEXT | plot-10 0
6 x TEXT | plot-10 1

# IfcDoor: arch-1200x2300 (14)
Type - OperationType: SINGLE_SWING_LEFT
OverallHeight: 2.3 m; OverallWidth: 1.2 m
Name | In
circulation sahn door | plot-0 0
circulation sahn door | plot-0 1
circulation sahn door | plot-1 0
living sahn door | plot-1 0
circulation sahn door | plot-1 1
circulation sahn door | plot-10 0
circulation sahn door | plot-10 1
living sahn door | plot-2 0
kitchen sahn door | plot-3 0
kitchen sahn door | plot-5 0
circulation sahn door | plot-6 0
circulation sahn door | plot-7 1
circulation sahn door | plot-8 0
circulation sahn door | plot-9 1

# IfcDoor: arch-1500x2300 (6)
Type - OperationType: SINGLE_SWING_LEFT
OverallHeight: 2.3 m; OverallWidth: 1.5 m
Name | In
circulation sahn door | plot-1 2
circulation sahn door | plot-2 1
circulation sahn door | plot-3 0
circulation sahn door | plot-6 0
circulation sahn door | plot-8 1
living sahn door | plot-9 0

# IfcDoor: arch-1500x2300-thin (2)
Type - OperationType: SINGLE_SWING_LEFT
OverallHeight: 2.3 m; OverallWidth: 1.5 m
Name | In
kitchen living inside door | plot-6 1
circulation inside door | plot-8 0

# IfcDoor: arch-1800x2300 (4)
Type - OperationType: SINGLE_SWING_LEFT
OverallHeight: 2.3 m; OverallWidth: 1.8 m
Name | In
kitchen sahn door | plot-10 0
kitchen sahn door | plot-2 0
circulation sahn door | plot-3 1
circulation sahn door | plot-4 0

# IfcDoor: arch-1800x2300-thin, circulation inside door
In: plot-3 0
Type - OperationType: SINGLE_SWING_LEFT
OverallHeight: 2.3 m; OverallWidth: 1.8 m

# IfcDoor: arch-2100x2300-thin (3)
Type - OperationType: SINGLE_SWING_LEFT
OverallHeight: 2.3 m; OverallWidth: 2.1 m
Name | In
kitchen living inside door | plot-3 0
living inside door | plot-4 1
kitchen living inside door | plot-5 0

# IfcDoor: arch-2400x2300-thin (15)
Type - OperationType: SINGLE_SWING_LEFT
OverallHeight: 2.3 m; OverallWidth: 2.4 m
Name | In
circulation inside door | plot-0 0
kitchen living inside door | plot-0 0
kitchen living inside door | plot-1 1
living inside door | plot-1 1
kitchen living inside door | plot-10 0
kitchen living inside door | plot-2 0
kitchen living inside door | plot-4 0
circulation inside door | plot-5 0
circulation inside door | plot-6 0
living inside door | plot-6 1
circulation inside door | plot-7 0
kitchen living inside door | plot-7 0
kitchen living inside door | plot-8 0
kitchen living inside door | plot-9 0
circulation inside door | plot-9 1

# IfcDoor: arch-800x2300 (21)
Type - OperationType: SINGLE_SWING_LEFT
OverallHeight: 2.3 m; OverallWidth: 0.8 m
Name | In
living sahn door | plot-0 0
kitchen sahn door | plot-0 0
living sahn door | plot-10 0
circulation sahn door | plot-10 0
2 x circulation sahn door | plot-2 0
circulation sahn door | plot-3 0
circulation sahn door | plot-4 0
2 x circulation sahn door | plot-5 0
living sahn door | plot-5 0
circulation sahn door | plot-5 1
circulation sahn door | plot-6 1
living sahn door | plot-7 0
kitchen sahn door | plot-7 0
circulation sahn door | plot-7 0
living sahn door | plot-8 0
kitchen sahn door | plot-8 0
circulation sahn door | plot-8 1
2 x circulation sahn door | plot-9 1

# IfcDoor: arch-900x2300 (15)
Type - OperationType: SINGLE_SWING_LEFT
OverallHeight: 2.3 m; OverallWidth: 0.9 m
Name | In
circulation sahn door | plot-0 0
circulation sahn door | plot-1 0
living sahn door | plot-10 1
circulation sahn door | plot-10 1
circulation sahn door | plot-2 1
living sahn door | plot-3 0
2 x circulation sahn door | plot-3 1
living sahn door | plot-4 0
circulation sahn door | plot-4 1
circulation sahn door | plot-4 2
circulation sahn door | plot-5 1
circulation sahn door | plot-8 0
kitchen sahn door | plot-9 0
circulation sahn door | plot-9 0

# IfcDoor: door-three-panel-taller (53)
Type - OperationType: SINGLE_SWING_LEFT
OverallHeight: 2.4 m; OverallWidth: 0.8 m
Name | In
bedroom sahn door | plot-0 0
bedroom inside door | plot-0 0
toilet inside door | plot-0 0
2 x bedroom sahn door | plot-0 1
toilet inside door | plot-0 1
toilet sahn door | plot-1 0
2 x bedroom inside door | plot-1 0
bedroom sahn door | plot-1 1
toilet inside door | plot-10 0
bedroom inside door | plot-10 0
bedroom sahn door | plot-10 1
bedroom sahn door | plot-2 0
toilet inside door | plot-2 0
bedroom inside door | plot-2 0
3 x bedroom sahn door | plot-2 1
toilet sahn door | plot-2 1
toilet sahn door | plot-3 0
bedroom inside door | plot-3 0
bedroom sahn door | plot-3 1
bedroom inside door | plot-3 1
bedroom sahn door | plot-4 0
2 x toilet inside door | plot-4 0
bedroom inside door | plot-4 0
bedroom sahn door | plot-4 1
bedroom sahn door | plot-4 2
bedroom inside door | plot-5 0
bedroom sahn door | plot-5 1
toilet inside door | plot-5 1
bedroom sahn door | plot-6 0
bedroom inside door | plot-6 0
toilet inside door | plot-6 0
bedroom sahn door | plot-6 1
2 x toilet sahn door | plot-7 0
bedroom inside door | plot-7 1
bedroom inside door | plot-7 2
bedroom sahn door | plot-8 0
toilet inside door | plot-8 0
bedroom inside door | plot-8 0
2 x bedroom sahn door | plot-8 1
2 x bedroom sahn door | plot-9 0
toilet inside door | plot-9 0
2 x bedroom sahn door | plot-9 1
2 x bedroom inside door | plot-9 1

# IfcDoor: gate-small, gate
In: plot-9 0
Type - OperationType: SINGLE_SWING_LEFT
OverallHeight: 1.81 m; OverallWidth: 1 m

# IfcDoor: tunis_entry_short (3)
Type - OperationType: SINGLE_SWING_LEFT
OverallHeight: 2.2 m; OverallWidth: 1.22 m
Name | In
house entrance | plot-1 0
house entrance | plot-10 0
house entrance | plot-4 0

# IfcDoor: tunis_entry_tall (8)
Type - OperationType: SINGLE_SWING_LEFT
OverallHeight: 2.545 m; OverallWidth: 1.22 m
Name | In
house entrance | plot-0 0
house entrance | plot-2 0
house entrance | plot-3 0
house entrance | plot-5 0
house entrance | plot-6 0
house entrance | plot-7 0
house entrance | plot-8 0
house entrance | plot-9 0

# IfcRoof (11)
PredefinedType: FREEFORM
Name | In
Roof | plot-0 1
Roof | plot-1 2
Roof | plot-10 1
Roof | plot-2 1
Roof | plot-3 1
Roof | plot-4 2
Roof | plot-5 1
Roof | plot-6 1
Roof | plot-7 2
Roof | plot-8 1
Roof | plot-9 1

# IfcRoof: eaves_0 (108)
Type - PredefinedType: FREEFORM
Name | In
8 x eaves_0 | plot-0 1
3 x eaves_0 | plot-1 2
12 x eaves_0 | plot-10 1
12 x eaves_0 | plot-2 1
12 x eaves_0 | plot-3 1
7 x eaves_0 | plot-4 2
11 x eaves_0 | plot-5 1
11 x eaves_0 | plot-6 1
5 x eaves_0 | plot-7 2
9 x eaves_0 | plot-8 1
18 x eaves_0 | plot-9 1

# IfcRoof: eaves_1 (108)
Type - PredefinedType: FREEFORM
Name | In
8 x eaves_1 | plot-0 1
3 x eaves_1 | plot-1 2
12 x eaves_1 | plot-10 1
12 x eaves_1 | plot-2 1
12 x eaves_1 | plot-3 1
7 x eaves_1 | plot-4 2
11 x eaves_1 | plot-5 1
11 x eaves_1 | plot-6 1
5 x eaves_1 | plot-7 2
9 x eaves_1 | plot-8 1
18 x eaves_1 | plot-9 1

# IfcRoof: roofline_0 (140)
Type - PredefinedType: FREEFORM
Name | In
14 x roofline_0 | plot-0 1
5 x roofline_0 | plot-1 2
13 x roofline_0 | plot-10 1
18 x roofline_0 | plot-2 1
14 x roofline_0 | plot-3 1
9 x roofline_0 | plot-4 2
13 x roofline_0 | plot-5 1
13 x roofline_0 | plot-6 1
7 x roofline_0 | plot-7 2
13 x roofline_0 | plot-8 1
21 x roofline_0 | plot-9 1

# IfcRoof: roofline_1 (140)
Type - PredefinedType: FREEFORM
Name | In
14 x roofline_1 | plot-0 1
5 x roofline_1 | plot-1 2
13 x roofline_1 | plot-10 1
18 x roofline_1 | plot-2 1
14 x roofline_1 | plot-3 1
9 x roofline_1 | plot-4 2
13 x roofline_1 | plot-5 1
13 x roofline_1 | plot-6 1
7 x roofline_1 | plot-7 2
13 x roofline_1 | plot-8 1
21 x roofline_1 | plot-9 1

# IfcSlab: Slab (204)
PredefinedType: FLOOR
Name | In
13 x My Slab | plot-0 0
7 x My Slab | plot-0 1
11 x My Slab | plot-1 0
6 x My Slab | plot-1 1
My Slab | plot-1 2
11 x My Slab | plot-10 0
5 x My Slab | plot-10 1
13 x My Slab | plot-2 0
9 x My Slab | plot-2 1
11 x My Slab | plot-3 0
7 x My Slab | plot-3 1
15 x My Slab | plot-4 0
4 x My Slab | plot-4 1
3 x My Slab | plot-4 2
9 x My Slab | plot-5 0
5 x My Slab | plot-5 1
9 x My Slab | plot-6 0
7 x My Slab | plot-6 1
11 x My Slab | plot-7 0
2 x My Slab | plot-7 1
3 x My Slab | plot-7 2
13 x My Slab | plot-8 0
5 x My Slab | plot-8 1
11 x My Slab | plot-9 0
13 x My Slab | plot-9 1

# IfcWall: exterior_0.08_0.25 (254)
Type - PredefinedType: SOLIDWALL; Material: Masonry 0.33 m
Name | In
12 x exterior | plot-0 0
8 x exterior | plot-0 1
12 x exterior | plot-1 0
9 x exterior | plot-1 1
3 x exterior | plot-1 2
14 x exterior | plot-10 0
12 x exterior | plot-10 1
9 x exterior | plot-2 0
12 x exterior | plot-2 1
10 x exterior | plot-3 0
12 x exterior | plot-3 1
15 x exterior | plot-4 0
6 x exterior | plot-4 1
7 x exterior | plot-4 2
10 x exterior | plot-5 0
11 x exterior | plot-5 1
10 x exterior | plot-6 0
11 x exterior | plot-6 1
7 x exterior | plot-7 0
5 x exterior | plot-7 1
5 x exterior | plot-7 2
12 x exterior | plot-8 0
9 x exterior | plot-8 1
15 x exterior | plot-9 0
18 x exterior | plot-9 1

# IfcWall: fence_-0.15_0.25, fence
In: plot-7 0
Type - PredefinedType: SOLIDWALL; Material: Masonry 0.1 m

# IfcWall: fence_0_0.25, fence
In: plot-9 0
Type - PredefinedType: SOLIDWALL; Material: Masonry 0.25 m

# IfcWall: interior_0.08_0.08 (94)
Type - PredefinedType: SOLIDWALL; Material: Masonry 0.16 m
Name | In
7 x interior | plot-0 0
3 x interior | plot-0 1
6 x interior | plot-1 0
3 x interior | plot-1 1
6 x interior | plot-10 0
interior | plot-10 1
7 x interior | plot-2 0
3 x interior | plot-2 1
6 x interior | plot-3 0
2 x interior | plot-3 1
8 x interior | plot-4 0
2 x interior | plot-4 1
5 x interior | plot-5 0
interior | plot-5 1
5 x interior | plot-6 0
3 x interior | plot-6 1
6 x interior | plot-7 0
interior | plot-7 1
interior | plot-7 2
7 x interior | plot-8 0
interior | plot-8 1
5 x interior | plot-9 0
5 x interior | plot-9 1

# IfcWall: parapet internal_0 (80)
Type - PredefinedType: PARAPET
Name | In
7 x parapet internal_0 | plot-0 1
4 x parapet internal_0 | plot-1 1
6 x parapet internal_0 | plot-1 2
7 x parapet internal_0 | plot-10 1
7 x parapet internal_0 | plot-2 1
7 x parapet internal_0 | plot-3 1
7 x parapet internal_0 | plot-4 1
3 x parapet internal_0 | plot-4 2
7 x parapet internal_0 | plot-5 1
3 x parapet internal_0 | plot-6 1
6 x parapet internal_0 | plot-7 1
8 x parapet internal_0 | plot-8 1
8 x parapet internal_0 | plot-9 1

# IfcWall: parapet internal_1 (80)
Type - PredefinedType: PARAPET
Name | In
7 x parapet internal_1 | plot-0 1
4 x parapet internal_1 | plot-1 1
6 x parapet internal_1 | plot-1 2
7 x parapet internal_1 | plot-10 1
7 x parapet internal_1 | plot-2 1
7 x parapet internal_1 | plot-3 1
7 x parapet internal_1 | plot-4 1
3 x parapet internal_1 | plot-4 2
7 x parapet internal_1 | plot-5 1
3 x parapet internal_1 | plot-6 1
6 x parapet internal_1 | plot-7 1
8 x parapet internal_1 | plot-8 1
8 x parapet internal_1 | plot-9 1

# IfcWall: parapet internal_2 (80)
Type - PredefinedType: PARAPET
Name | In
7 x parapet internal_2 | plot-0 1
4 x parapet internal_2 | plot-1 1
6 x parapet internal_2 | plot-1 2
7 x parapet internal_2 | plot-10 1
7 x parapet internal_2 | plot-2 1
7 x parapet internal_2 | plot-3 1
7 x parapet internal_2 | plot-4 1
3 x parapet internal_2 | plot-4 2
7 x parapet internal_2 | plot-5 1
3 x parapet internal_2 | plot-6 1
6 x parapet internal_2 | plot-7 1
8 x parapet internal_2 | plot-8 1
8 x parapet internal_2 | plot-9 1

# IfcWall: parapet party_0 (57)
Type - PredefinedType: PARAPET
Name | In
5 x parapet party_0 | plot-0 1
3 x parapet party_0 | plot-1 1
3 x parapet party_0 | plot-1 2
3 x parapet party_0 | plot-10 1
7 x parapet party_0 | plot-2 1
8 x parapet party_0 | plot-3 1
3 x parapet party_0 | plot-4 1
4 x parapet party_0 | plot-4 2
5 x parapet party_0 | plot-5 1
4 x parapet party_0 | plot-6 1
8 x parapet party_0 | plot-7 1
4 x parapet party_0 | plot-8 1

# IfcWall: parapet party_1 (57)
Type - PredefinedType: PARAPET
Name | In
5 x parapet party_1 | plot-0 1
3 x parapet party_1 | plot-1 1
3 x parapet party_1 | plot-1 2
3 x parapet party_1 | plot-10 1
7 x parapet party_1 | plot-2 1
8 x parapet party_1 | plot-3 1
3 x parapet party_1 | plot-4 1
4 x parapet party_1 | plot-4 2
5 x parapet party_1 | plot-5 1
4 x parapet party_1 | plot-6 1
8 x parapet party_1 | plot-7 1
4 x parapet party_1 | plot-8 1

# IfcWall: parapet street_0 (48)
Type - PredefinedType: PARAPET
Name | In
4 x parapet street_0 | plot-0 1
5 x parapet street_0 | plot-1 1
5 x parapet street_0 | plot-1 2
7 x parapet street_0 | plot-10 1
3 x parapet street_0 | plot-3 1
8 x parapet street_0 | plot-4 1
3 x parapet street_0 | plot-5 1
5 x parapet street_0 | plot-8 1
8 x parapet street_0 | plot-9 1

# IfcWall: parapet street_1 (48)
Type - PredefinedType: PARAPET
Name | In
4 x parapet street_1 | plot-0 1
5 x parapet street_1 | plot-1 1
5 x parapet street_1 | plot-1 2
7 x parapet street_1 | plot-10 1
3 x parapet street_1 | plot-3 1
8 x parapet street_1 | plot-4 1
3 x parapet street_1 | plot-5 1
5 x parapet street_1 | plot-8 1
8 x parapet street_1 | plot-9 1

# IfcWall: party_0.08_0.25 (100)
Type - PredefinedType: SOLIDWALL; Material: Masonry 0.33 m
Name | In
8 x party | plot-0 0
6 x party | plot-0 1
4 x party | plot-1 0
3 x party | plot-1 1
2 x party | plot-1 2
2 x party | plot-10 0
party | plot-10 1
9 x party | plot-2 0
6 x party | plot-2 1
6 x party | plot-3 0
2 x party | plot-3 1
5 x party | plot-4 0
4 x party | plot-4 1
2 x party | plot-4 2
4 x party | plot-5 0
2 x party | plot-5 1
4 x party | plot-6 0
2 x party | plot-6 1
8 x party | plot-7 0
2 x party | plot-7 1
2 x party | plot-7 2
6 x party | plot-8 0
4 x party | plot-8 1
3 x party | plot-9 0
3 x party | plot-9 1

# IfcWindow: barred_window (62)
Type - PartitioningType: DOUBLE_PANEL_HORIZONTAL
OverallHeight: 0.4 m; OverallWidth: 0.4 m
Name | In
bedroom street window | plot-0 0
circulation street window | plot-0 0
living street window | plot-1 0
toilet street window | plot-1 0
2 x bedroom street window | plot-1 0
2 x circulation street window | plot-1 0
circulation street window | plot-10 0
toilet street window | plot-10 0
5 x living street window | plot-10 0
2 x kitchen street window | plot-10 0
2 x bedroom street window | plot-10 0
2 x living street window | plot-2 0
2 x living street window | plot-3 0
5 x circulation street window | plot-3 0
4 x bedroom street window | plot-4 0
2 x toilet street window | plot-4 0
2 x kitchen street window | plot-4 0
living street window | plot-5 0
kitchen street window | plot-5 0
3 x circulation street window | plot-5 0
3 x circulation street window | plot-6 0
toilet street window | plot-6 0
bedroom street window | plot-6 0
circulation street window | plot-7 0
4 x circulation street window | plot-8 0
toilet street window | plot-8 0
kitchen street window | plot-8 0
2 x kitchen street window | plot-9 0
2 x living street window | plot-9 0
4 x bedroom street window | plot-9 0
toilet street window | plot-9 0

# IfcWindow: shuttered_big (17)
Type - PartitioningType: DOUBLE_PANEL_HORIZONTAL
OverallHeight: 1.82 m; OverallWidth: 0.91 m
Name | In
2 x bedroom sahn window | plot-0 0
2 x toilet sahn window | plot-0 0
toilet sahn window | plot-2 0
bedroom sahn window | plot-2 0
bedroom sahn window | plot-3 0
bedroom sahn window | plot-5 0
2 x toilet sahn window | plot-6 0
2 x bedroom sahn window | plot-8 0
2 x toilet sahn window | plot-8 0
2 x bedroom sahn window | plot-9 0
toilet sahn window | plot-9 0

# IfcWindow: shuttered_big_narrow (3)
Type - PartitioningType: DOUBLE_PANEL_HORIZONTAL
OverallHeight: 1.82 m; OverallWidth: 0.61 m
Name | In
toilet sahn window | plot-3 0
bedroom sahn window | plot-6 0
bedroom sahn window | plot-9 0

# IfcWindow: shuttered_shorter (148)
Type - PartitioningType: DOUBLE_PANEL_HORIZONTAL
OverallHeight: 1.445 m; OverallWidth: 0.91 m
Name | In
bedroom sahn window | plot-0 1
2 x toilet outside window | plot-0 1
circulation sahn window | plot-0 1
circulation outside window | plot-0 1
2 x bedroom sahn window | plot-1 0
3 x living outside window | plot-1 1
2 x kitchen outside window | plot-1 1
2 x bedroom outside window | plot-1 1
bedroom sahn window | plot-1 1
circulation outside window | plot-1 1
2 x circulation outside window | plot-1 2
2 x toilet sahn window | plot-10 0
bedroom sahn window | plot-10 0
6 x living outside window | plot-10 1
2 x bedroom outside window | plot-10 1
3 x bedroom sahn window | plot-10 1
living sahn window | plot-10 1
circulation outside window | plot-10 1
circulation sahn window | plot-10 1
3 x bedroom outside window | plot-2 1
2 x toilet outside window | plot-2 1
circulation sahn window | plot-2 1
4 x bedroom sahn window | plot-2 1
toilet sahn window | plot-2 1
2 x circulation sahn window | plot-3 1
3 x bedroom sahn window | plot-3 1
5 x bedroom outside window | plot-3 1
3 x circulation outside window | plot-3 1
2 x toilet sahn window | plot-4 0
bedroom sahn window | plot-4 0
3 x circulation sahn window | plot-4 1
living sahn window | plot-4 1
3 x bedroom outside window | plot-4 1
2 x bedroom sahn window | plot-4 2
4 x bedroom outside window | plot-4 2
circulation sahn window | plot-4 2
3 x circulation outside window | plot-4 2
toilet sahn window | plot-5 1
5 x circulation outside window | plot-5 1
toilet outside window | plot-5 1
3 x bedroom outside window | plot-5 1
2 x bedroom sahn window | plot-5 1
2 x bedroom sahn window | plot-6 1
2 x kitchen sahn window | plot-6 1
living sahn window | plot-6 1
2 x circulation sahn window | plot-6 1
circulation outside window | plot-6 1
5 x living outside window | plot-6 1
2 x kitchen outside window | plot-6 1
2 x bedroom outside window | plot-6 1
2 x bedroom sahn window | plot-7 1
circulation sahn window | plot-7 1
circulation outside window | plot-7 1
2 x bedroom outside window | plot-7 1
2 x circulation outside window | plot-7 2
2 x bedroom outside window | plot-7 2
2 x bedroom sahn window | plot-7 2
circulation sahn window | plot-7 2
6 x circulation outside window | plot-8 1
2 x bedroom sahn window | plot-8 1
3 x bedroom outside window | plot-8 1
12 x bedroom outside window | plot-9 1
bedroom sahn window | plot-9 1
3 x circulation outside window | plot-9 1

# IfcWindow: shuttered_shorter_narrow (6)
Type - PartitioningType: DOUBLE_PANEL_HORIZONTAL
OverallHeight: 1.445 m; OverallWidth: 0.61 m
Name | In
bedroom outside window | plot-0 1
toilet sahn window | plot-1 0
2 x bedroom sahn window | plot-2 1
bedroom sahn window | plot-4 0
bedroom sahn window | plot-4 1
